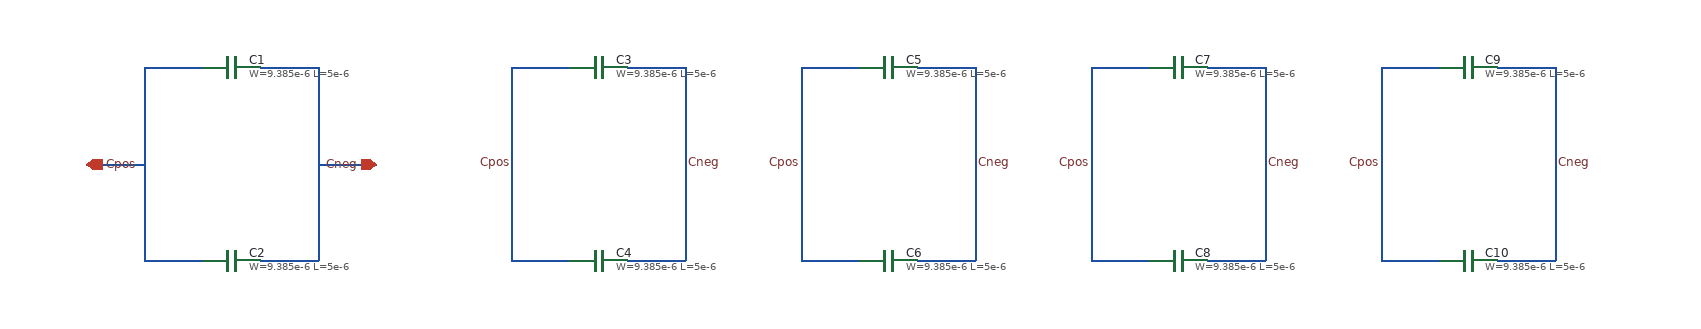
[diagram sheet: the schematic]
v {xschem version=3.4.8RC file_version=1.3}
G {}
K {}
V {}
S {}
F {}
E {}
N 2420 -1000 2480 -1000 {lab=Cneg}
N 2300 -1000 2360 -1000 {lab=Cpos}
N 2300 -800 2360 -800 {lab=Cpos}
N 2420 -800 2480 -800 {lab=Cneg}
N 2040 -1000 2100 -1000 {lab=Cneg}
N 1920 -1000 1980 -1000 {lab=Cpos}
N 1920 -800 1980 -800 {lab=Cpos}
N 2040 -800 2100 -800 {lab=Cneg}
N 2100 -1000 2100 -800 {lab=Cneg}
N 1920 -1000 1920 -800 {lab=Cpos}
N 1860 -900 1920 -900 {lab=Cpos}
N 2100 -900 2160 -900 {lab=Cneg}
N 2300 -1000 2300 -800 {lab=Cpos}
N 2480 -1000 2480 -800 {lab=Cneg}
N 2720 -1000 2780 -1000 {lab=Cneg}
N 2600 -1000 2660 -1000 {lab=Cpos}
N 2600 -800 2660 -800 {lab=Cpos}
N 2720 -800 2780 -800 {lab=Cneg}
N 2600 -1000 2600 -800 {lab=Cpos}
N 2780 -1000 2780 -800 {lab=Cneg}
N 3020 -1000 3080 -1000 {lab=Cneg}
N 2900 -1000 2960 -1000 {lab=Cpos}
N 2900 -800 2960 -800 {lab=Cpos}
N 3020 -800 3080 -800 {lab=Cneg}
N 2900 -1000 2900 -800 {lab=Cpos}
N 3080 -1000 3080 -800 {lab=Cneg}
N 3320 -1000 3380 -1000 {lab=Cneg}
N 3200 -1000 3260 -1000 {lab=Cpos}
N 3200 -800 3260 -800 {lab=Cpos}
N 3320 -800 3380 -800 {lab=Cneg}
N 3200 -1000 3200 -800 {lab=Cpos}
N 3380 -1000 3380 -800 {lab=Cneg}
C {iopin.sym} 1860 -900 0 1 {name=p3 lab=Cpos}
C {iopin.sym} 2160 -900 0 0 {name=p4 lab=Cneg}
C {lab_pin.sym} 2300 -900 0 0 {name=p20 lab=Cpos}
C {lab_pin.sym} 2480 -900 0 1 {name=p5 lab=Cneg}
C {lab_pin.sym} 2600 -900 0 0 {name=p1 lab=Cpos}
C {lab_pin.sym} 2780 -900 0 1 {name=p2 lab=Cneg}
C {lab_pin.sym} 2900 -900 0 0 {name=p6 lab=Cpos}
C {lab_pin.sym} 3080 -900 0 1 {name=p7 lab=Cneg}
C {lab_pin.sym} 3200 -900 0 0 {name=p8 lab=Cpos}
C {lab_pin.sym} 3380 -900 0 1 {name=p9 lab=Cneg}
C {symbols/cap_mim_2f0fF.sym} 2010 -1000 3 0 {name=C1
W=9.385e-6
L=5e-6
model=cap_mim_2f0fF
spiceprefix=X
m=1}
C {symbols/cap_mim_2f0fF.sym} 2010 -800 3 1 {name=C2
W=9.385e-6
L=5e-6
model=cap_mim_2f0fF
spiceprefix=X
m=1}
C {symbols/cap_mim_2f0fF.sym} 2390 -1000 3 0 {name=C3
W=9.385e-6
L=5e-6
model=cap_mim_2f0fF
spiceprefix=X
m=1}
C {symbols/cap_mim_2f0fF.sym} 2390 -800 3 1 {name=C4
W=9.385e-6
L=5e-6
model=cap_mim_2f0fF
spiceprefix=X
m=1}
C {symbols/cap_mim_2f0fF.sym} 2690 -1000 3 0 {name=C5
W=9.385e-6
L=5e-6
model=cap_mim_2f0fF
spiceprefix=X
m=1}
C {symbols/cap_mim_2f0fF.sym} 2690 -800 3 1 {name=C6
W=9.385e-6
L=5e-6
model=cap_mim_2f0fF
spiceprefix=X
m=1}
C {symbols/cap_mim_2f0fF.sym} 2990 -1000 3 0 {name=C7
W=9.385e-6
L=5e-6
model=cap_mim_2f0fF
spiceprefix=X
m=1}
C {symbols/cap_mim_2f0fF.sym} 2990 -800 3 1 {name=C8
W=9.385e-6
L=5e-6
model=cap_mim_2f0fF
spiceprefix=X
m=1}
C {symbols/cap_mim_2f0fF.sym} 3290 -1000 3 0 {name=C9
W=9.385e-6
L=5e-6
model=cap_mim_2f0fF
spiceprefix=X
m=1}
C {symbols/cap_mim_2f0fF.sym} 3290 -800 3 1 {name=C10
W=9.385e-6
L=5e-6
model=cap_mim_2f0fF
spiceprefix=X
m=1}
C {title.sym} 2040 -560 0 0 {name=l1 author="Sayyad Arif"}
